VERSION 5.4 ;
NAMESCASESENSITIVE ON ;
BUSBITCHARS "[]" ;
DIVIDERCHAR "/" ;
UNITS
  DATABASE MICRONS 2000 ;
END UNITS
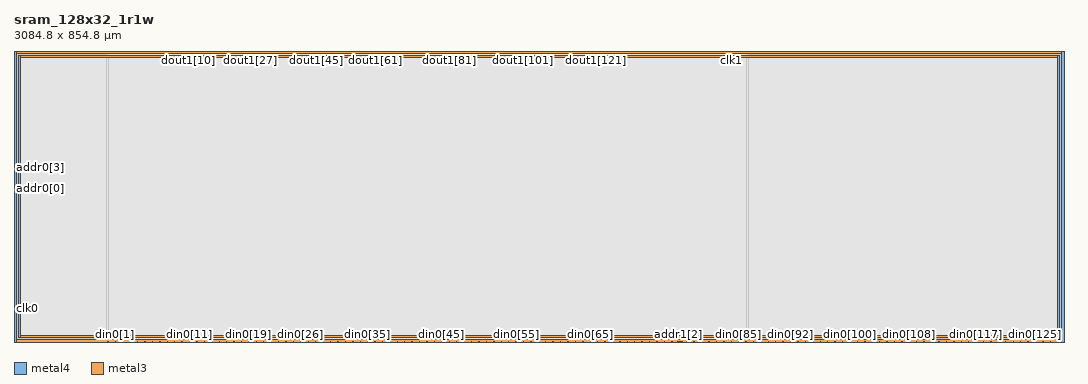
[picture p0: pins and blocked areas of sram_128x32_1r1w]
MACRO sram_128x32_1r1w
   CLASS BLOCK ;
   SIZE 3084.8 BY 854.8 ;
   SYMMETRY X Y R90 ;
   PIN din0[0]
      DIRECTION INPUT ;
      PORT
         LAYER metal4 ;
         RECT  275.4 0.0 276.6 1.2 ;
      END
   END din0[0]
   PIN din0[1]
      DIRECTION INPUT ;
      PORT
         LAYER metal4 ;
         RECT  297.2 0.0 298.4 1.2 ;
      END
   END din0[1]
   PIN din0[2]
      DIRECTION INPUT ;
      PORT
         LAYER metal4 ;
         RECT  319.0 0.0 320.2 1.2 ;
      END
   END din0[2]
   PIN din0[3]
      DIRECTION INPUT ;
      PORT
         LAYER metal4 ;
         RECT  340.8 0.0 342.0 1.2 ;
      END
   END din0[3]
   PIN din0[4]
      DIRECTION INPUT ;
      PORT
         LAYER metal4 ;
         RECT  362.6 0.0 363.8 1.2 ;
      END
   END din0[4]
   PIN din0[5]
      DIRECTION INPUT ;
      PORT
         LAYER metal4 ;
         RECT  384.4 0.0 385.6 1.2 ;
      END
   END din0[5]
   PIN din0[6]
      DIRECTION INPUT ;
      PORT
         LAYER metal4 ;
         RECT  406.2 0.0 407.4 1.2 ;
      END
   END din0[6]
   PIN din0[7]
      DIRECTION INPUT ;
      PORT
         LAYER metal4 ;
         RECT  428.0 0.0 429.2 1.2 ;
      END
   END din0[7]
   PIN din0[8]
      DIRECTION INPUT ;
      PORT
         LAYER metal4 ;
         RECT  449.8 0.0 451.0 1.2 ;
      END
   END din0[8]
   PIN din0[9]
      DIRECTION INPUT ;
      PORT
         LAYER metal4 ;
         RECT  471.6 0.0 472.8 1.2 ;
      END
   END din0[9]
   PIN din0[10]
      DIRECTION INPUT ;
      PORT
         LAYER metal4 ;
         RECT  493.4 0.0 494.6 1.2 ;
      END
   END din0[10]
   PIN din0[11]
      DIRECTION INPUT ;
      PORT
         LAYER metal4 ;
         RECT  515.2 0.0 516.4 1.2 ;
      END
   END din0[11]
   PIN din0[12]
      DIRECTION INPUT ;
      PORT
         LAYER metal4 ;
         RECT  537.0 0.0 538.2 1.2 ;
      END
   END din0[12]
   PIN din0[13]
      DIRECTION INPUT ;
      PORT
         LAYER metal4 ;
         RECT  558.8 0.0 560.0 1.2 ;
      END
   END din0[13]
   PIN din0[14]
      DIRECTION INPUT ;
      PORT
         LAYER metal4 ;
         RECT  580.6 0.0 581.8 1.2 ;
      END
   END din0[14]
   PIN din0[15]
      DIRECTION INPUT ;
      PORT
         LAYER metal4 ;
         RECT  602.4 0.0 603.6 1.2 ;
      END
   END din0[15]
   PIN din0[16]
      DIRECTION INPUT ;
      PORT
         LAYER metal4 ;
         RECT  624.2 0.0 625.4 1.2 ;
      END
   END din0[16]
   PIN din0[17]
      DIRECTION INPUT ;
      PORT
         LAYER metal4 ;
         RECT  646.0 0.0 647.2 1.2 ;
      END
   END din0[17]
   PIN din0[18]
      DIRECTION INPUT ;
      PORT
         LAYER metal4 ;
         RECT  667.8 0.0 669.0 1.2 ;
      END
   END din0[18]
   PIN din0[19]
      DIRECTION INPUT ;
      PORT
         LAYER metal4 ;
         RECT  689.6 0.0 690.8 1.2 ;
      END
   END din0[19]
   PIN din0[20]
      DIRECTION INPUT ;
      PORT
         LAYER metal4 ;
         RECT  711.4 0.0 712.6 1.2 ;
      END
   END din0[20]
   PIN din0[21]
      DIRECTION INPUT ;
      PORT
         LAYER metal4 ;
         RECT  733.2 0.0 734.4 1.2 ;
      END
   END din0[21]
   PIN din0[22]
      DIRECTION INPUT ;
      PORT
         LAYER metal4 ;
         RECT  755.0 0.0 756.2 1.2 ;
      END
   END din0[22]
   PIN din0[23]
      DIRECTION INPUT ;
      PORT
         LAYER metal4 ;
         RECT  776.8 0.0 778.0 1.2 ;
      END
   END din0[23]
   PIN din0[24]
      DIRECTION INPUT ;
      PORT
         LAYER metal4 ;
         RECT  798.6 0.0 799.8 1.2 ;
      END
   END din0[24]
   PIN din0[25]
      DIRECTION INPUT ;
      PORT
         LAYER metal4 ;
         RECT  820.4 0.0 821.6 1.2 ;
      END
   END din0[25]
   PIN din0[26]
      DIRECTION INPUT ;
      PORT
         LAYER metal4 ;
         RECT  842.2 0.0 843.4 1.2 ;
      END
   END din0[26]
   PIN din0[27]
      DIRECTION INPUT ;
      PORT
         LAYER metal4 ;
         RECT  864.0 0.0 865.2 1.2 ;
      END
   END din0[27]
   PIN din0[28]
      DIRECTION INPUT ;
      PORT
         LAYER metal4 ;
         RECT  885.8 0.0 887.0 1.2 ;
      END
   END din0[28]
   PIN din0[29]
      DIRECTION INPUT ;
      PORT
         LAYER metal4 ;
         RECT  907.6 0.0 908.8 1.2 ;
      END
   END din0[29]
   PIN din0[30]
      DIRECTION INPUT ;
      PORT
         LAYER metal4 ;
         RECT  929.4 0.0 930.6 1.2 ;
      END
   END din0[30]
   PIN din0[31]
      DIRECTION INPUT ;
      PORT
         LAYER metal4 ;
         RECT  951.2 0.0 952.4 1.2 ;
      END
   END din0[31]
   PIN din0[32]
      DIRECTION INPUT ;
      PORT
         LAYER metal4 ;
         RECT  973.0 0.0 974.2 1.2 ;
      END
   END din0[32]
   PIN din0[33]
      DIRECTION INPUT ;
      PORT
         LAYER metal4 ;
         RECT  994.8 0.0 996.0 1.2 ;
      END
   END din0[33]
   PIN din0[34]
      DIRECTION INPUT ;
      PORT
         LAYER metal4 ;
         RECT  1016.6 0.0 1017.8 1.2 ;
      END
   END din0[34]
   PIN din0[35]
      DIRECTION INPUT ;
      PORT
         LAYER metal4 ;
         RECT  1038.4 0.0 1039.6 1.2 ;
      END
   END din0[35]
   PIN din0[36]
      DIRECTION INPUT ;
      PORT
         LAYER metal4 ;
         RECT  1060.2 0.0 1061.4 1.2 ;
      END
   END din0[36]
   PIN din0[37]
      DIRECTION INPUT ;
      PORT
         LAYER metal4 ;
         RECT  1082.0 0.0 1083.2 1.2 ;
      END
   END din0[37]
   PIN din0[38]
      DIRECTION INPUT ;
      PORT
         LAYER metal4 ;
         RECT  1103.8 0.0 1105.0 1.2 ;
      END
   END din0[38]
   PIN din0[39]
      DIRECTION INPUT ;
      PORT
         LAYER metal4 ;
         RECT  1125.6 0.0 1126.8 1.2 ;
      END
   END din0[39]
   PIN din0[40]
      DIRECTION INPUT ;
      PORT
         LAYER metal4 ;
         RECT  1147.4 0.0 1148.6 1.2 ;
      END
   END din0[40]
   PIN din0[41]
      DIRECTION INPUT ;
      PORT
         LAYER metal4 ;
         RECT  1169.2 0.0 1170.4 1.2 ;
      END
   END din0[41]
   PIN din0[42]
      DIRECTION INPUT ;
      PORT
         LAYER metal4 ;
         RECT  1191.0 0.0 1192.2 1.2 ;
      END
   END din0[42]
   PIN din0[43]
      DIRECTION INPUT ;
      PORT
         LAYER metal4 ;
         RECT  1212.8 0.0 1214.0 1.2 ;
      END
   END din0[43]
   PIN din0[44]
      DIRECTION INPUT ;
      PORT
         LAYER metal4 ;
         RECT  1234.6 0.0 1235.8 1.2 ;
      END
   END din0[44]
   PIN din0[45]
      DIRECTION INPUT ;
      PORT
         LAYER metal4 ;
         RECT  1256.4 0.0 1257.6 1.2 ;
      END
   END din0[45]
   PIN din0[46]
      DIRECTION INPUT ;
      PORT
         LAYER metal4 ;
         RECT  1278.2 0.0 1279.4 1.2 ;
      END
   END din0[46]
   PIN din0[47]
      DIRECTION INPUT ;
      PORT
         LAYER metal4 ;
         RECT  1300.0 0.0 1301.2 1.2 ;
      END
   END din0[47]
   PIN din0[48]
      DIRECTION INPUT ;
      PORT
         LAYER metal4 ;
         RECT  1321.8 0.0 1323.0 1.2 ;
      END
   END din0[48]
   PIN din0[49]
      DIRECTION INPUT ;
      PORT
         LAYER metal4 ;
         RECT  1343.6 0.0 1344.8 1.2 ;
      END
   END din0[49]
   PIN din0[50]
      DIRECTION INPUT ;
      PORT
         LAYER metal4 ;
         RECT  1365.4 0.0 1366.6 1.2 ;
      END
   END din0[50]
   PIN din0[51]
      DIRECTION INPUT ;
      PORT
         LAYER metal4 ;
         RECT  1387.2 0.0 1388.4 1.2 ;
      END
   END din0[51]
   PIN din0[52]
      DIRECTION INPUT ;
      PORT
         LAYER metal4 ;
         RECT  1409.0 0.0 1410.2 1.2 ;
      END
   END din0[52]
   PIN din0[53]
      DIRECTION INPUT ;
      PORT
         LAYER metal4 ;
         RECT  1430.8 0.0 1432.0 1.2 ;
      END
   END din0[53]
   PIN din0[54]
      DIRECTION INPUT ;
      PORT
         LAYER metal4 ;
         RECT  1452.6 0.0 1453.8 1.2 ;
      END
   END din0[54]
   PIN din0[55]
      DIRECTION INPUT ;
      PORT
         LAYER metal4 ;
         RECT  1474.4 0.0 1475.6 1.2 ;
      END
   END din0[55]
   PIN din0[56]
      DIRECTION INPUT ;
      PORT
         LAYER metal4 ;
         RECT  1496.2 0.0 1497.4 1.2 ;
      END
   END din0[56]
   PIN din0[57]
      DIRECTION INPUT ;
      PORT
         LAYER metal4 ;
         RECT  1518.0 0.0 1519.2 1.2 ;
      END
   END din0[57]
   PIN din0[58]
      DIRECTION INPUT ;
      PORT
         LAYER metal4 ;
         RECT  1539.8 0.0 1541.0 1.2 ;
      END
   END din0[58]
   PIN din0[59]
      DIRECTION INPUT ;
      PORT
         LAYER metal4 ;
         RECT  1561.6 0.0 1562.8 1.2 ;
      END
   END din0[59]
   PIN din0[60]
      DIRECTION INPUT ;
      PORT
         LAYER metal4 ;
         RECT  1583.4 0.0 1584.6 1.2 ;
      END
   END din0[60]
   PIN din0[61]
      DIRECTION INPUT ;
      PORT
         LAYER metal4 ;
         RECT  1605.2 0.0 1606.4 1.2 ;
      END
   END din0[61]
   PIN din0[62]
      DIRECTION INPUT ;
      PORT
         LAYER metal4 ;
         RECT  1627.0 0.0 1628.2 1.2 ;
      END
   END din0[62]
   PIN din0[63]
      DIRECTION INPUT ;
      PORT
         LAYER metal4 ;
         RECT  1648.8 0.0 1650.0 1.2 ;
      END
   END din0[63]
   PIN din0[64]
      DIRECTION INPUT ;
      PORT
         LAYER metal4 ;
         RECT  1670.6 0.0 1671.8 1.2 ;
      END
   END din0[64]
   PIN din0[65]
      DIRECTION INPUT ;
      PORT
         LAYER metal4 ;
         RECT  1692.4 0.0 1693.6 1.2 ;
      END
   END din0[65]
   PIN din0[66]
      DIRECTION INPUT ;
      PORT
         LAYER metal4 ;
         RECT  1714.2 0.0 1715.4 1.2 ;
      END
   END din0[66]
   PIN din0[67]
      DIRECTION INPUT ;
      PORT
         LAYER metal4 ;
         RECT  1736.0 0.0 1737.2 1.2 ;
      END
   END din0[67]
   PIN din0[68]
      DIRECTION INPUT ;
      PORT
         LAYER metal4 ;
         RECT  1757.8 0.0 1759.0 1.2 ;
      END
   END din0[68]
   PIN din0[69]
      DIRECTION INPUT ;
      PORT
         LAYER metal4 ;
         RECT  1779.6 0.0 1780.8 1.2 ;
      END
   END din0[69]
   PIN din0[70]
      DIRECTION INPUT ;
      PORT
         LAYER metal4 ;
         RECT  1801.4 0.0 1802.6 1.2 ;
      END
   END din0[70]
   PIN din0[71]
      DIRECTION INPUT ;
      PORT
         LAYER metal4 ;
         RECT  1823.2 0.0 1824.4 1.2 ;
      END
   END din0[71]
   PIN din0[72]
      DIRECTION INPUT ;
      PORT
         LAYER metal4 ;
         RECT  1845.0 0.0 1846.2 1.2 ;
      END
   END din0[72]
   PIN din0[73]
      DIRECTION INPUT ;
      PORT
         LAYER metal4 ;
         RECT  1866.8 0.0 1868.0 1.2 ;
      END
   END din0[73]
   PIN din0[74]
      DIRECTION INPUT ;
      PORT
         LAYER metal4 ;
         RECT  1888.6 0.0 1889.8 1.2 ;
      END
   END din0[74]
   PIN din0[75]
      DIRECTION INPUT ;
      PORT
         LAYER metal4 ;
         RECT  1910.4 0.0 1911.6 1.2 ;
      END
   END din0[75]
   PIN din0[76]
      DIRECTION INPUT ;
      PORT
         LAYER metal4 ;
         RECT  1932.2 0.0 1933.4 1.2 ;
      END
   END din0[76]
   PIN din0[77]
      DIRECTION INPUT ;
      PORT
         LAYER metal4 ;
         RECT  1954.0 0.0 1955.2 1.2 ;
      END
   END din0[77]
   PIN din0[78]
      DIRECTION INPUT ;
      PORT
         LAYER metal4 ;
         RECT  1975.8 0.0 1977.0 1.2 ;
      END
   END din0[78]
   PIN din0[79]
      DIRECTION INPUT ;
      PORT
         LAYER metal4 ;
         RECT  1997.6 0.0 1998.8 1.2 ;
      END
   END din0[79]
   PIN din0[80]
      DIRECTION INPUT ;
      PORT
         LAYER metal4 ;
         RECT  2019.4 0.0 2020.6 1.2 ;
      END
   END din0[80]
   PIN din0[81]
      DIRECTION INPUT ;
      PORT
         LAYER metal4 ;
         RECT  2041.2 0.0 2042.4 1.2 ;
      END
   END din0[81]
   PIN din0[82]
      DIRECTION INPUT ;
      PORT
         LAYER metal4 ;
         RECT  2063.0 0.0 2064.2 1.2 ;
      END
   END din0[82]
   PIN din0[83]
      DIRECTION INPUT ;
      PORT
         LAYER metal4 ;
         RECT  2084.8 0.0 2086.0 1.2 ;
      END
   END din0[83]
   PIN din0[84]
      DIRECTION INPUT ;
      PORT
         LAYER metal4 ;
         RECT  2106.6 0.0 2107.8 1.2 ;
      END
   END din0[84]
   PIN din0[85]
      DIRECTION INPUT ;
      PORT
         LAYER metal4 ;
         RECT  2128.4 0.0 2129.6 1.2 ;
      END
   END din0[85]
   PIN din0[86]
      DIRECTION INPUT ;
      PORT
         LAYER metal4 ;
         RECT  2150.2 0.0 2151.4 1.2 ;
      END
   END din0[86]
   PIN din0[87]
      DIRECTION INPUT ;
      PORT
         LAYER metal4 ;
         RECT  2172.0 0.0 2173.2 1.2 ;
      END
   END din0[87]
   PIN din0[88]
      DIRECTION INPUT ;
      PORT
         LAYER metal4 ;
         RECT  2193.8 0.0 2195.0 1.2 ;
      END
   END din0[88]
   PIN din0[89]
      DIRECTION INPUT ;
      PORT
         LAYER metal4 ;
         RECT  2215.6 0.0 2216.8 1.2 ;
      END
   END din0[89]
   PIN din0[90]
      DIRECTION INPUT ;
      PORT
         LAYER metal4 ;
         RECT  2237.4 0.0 2238.6 1.2 ;
      END
   END din0[90]
   PIN din0[91]
      DIRECTION INPUT ;
      PORT
         LAYER metal4 ;
         RECT  2259.2 0.0 2260.4 1.2 ;
      END
   END din0[91]
   PIN din0[92]
      DIRECTION INPUT ;
      PORT
         LAYER metal4 ;
         RECT  2281.0 0.0 2282.2 1.2 ;
      END
   END din0[92]
   PIN din0[93]
      DIRECTION INPUT ;
      PORT
         LAYER metal4 ;
         RECT  2302.8 0.0 2304.0 1.2 ;
      END
   END din0[93]
   PIN din0[94]
      DIRECTION INPUT ;
      PORT
         LAYER metal4 ;
         RECT  2324.6 0.0 2325.8 1.2 ;
      END
   END din0[94]
   PIN din0[95]
      DIRECTION INPUT ;
      PORT
         LAYER metal4 ;
         RECT  2346.4 0.0 2347.6 1.2 ;
      END
   END din0[95]
   PIN din0[96]
      DIRECTION INPUT ;
      PORT
         LAYER metal4 ;
         RECT  2368.2 0.0 2369.4 1.2 ;
      END
   END din0[96]
   PIN din0[97]
      DIRECTION INPUT ;
      PORT
         LAYER metal4 ;
         RECT  2390.0 0.0 2391.2 1.2 ;
      END
   END din0[97]
   PIN din0[98]
      DIRECTION INPUT ;
      PORT
         LAYER metal4 ;
         RECT  2411.8 0.0 2413.0 1.2 ;
      END
   END din0[98]
   PIN din0[99]
      DIRECTION INPUT ;
      PORT
         LAYER metal4 ;
         RECT  2433.6 0.0 2434.8 1.2 ;
      END
   END din0[99]
   PIN din0[100]
      DIRECTION INPUT ;
      PORT
         LAYER metal4 ;
         RECT  2455.4 0.0 2456.6 1.2 ;
      END
   END din0[100]
   PIN din0[101]
      DIRECTION INPUT ;
      PORT
         LAYER metal4 ;
         RECT  2477.2 0.0 2478.4 1.2 ;
      END
   END din0[101]
   PIN din0[102]
      DIRECTION INPUT ;
      PORT
         LAYER metal4 ;
         RECT  2499.0 0.0 2500.2 1.2 ;
      END
   END din0[102]
   PIN din0[103]
      DIRECTION INPUT ;
      PORT
         LAYER metal4 ;
         RECT  2520.8 0.0 2522.0 1.2 ;
      END
   END din0[103]
   PIN din0[104]
      DIRECTION INPUT ;
      PORT
         LAYER metal4 ;
         RECT  2542.6 0.0 2543.8 1.2 ;
      END
   END din0[104]
   PIN din0[105]
      DIRECTION INPUT ;
      PORT
         LAYER metal4 ;
         RECT  2564.4 0.0 2565.6 1.2 ;
      END
   END din0[105]
   PIN din0[106]
      DIRECTION INPUT ;
      PORT
         LAYER metal4 ;
         RECT  2586.2 0.0 2587.4 1.2 ;
      END
   END din0[106]
   PIN din0[107]
      DIRECTION INPUT ;
      PORT
         LAYER metal4 ;
         RECT  2608.0 0.0 2609.2 1.2 ;
      END
   END din0[107]
   PIN din0[108]
      DIRECTION INPUT ;
      PORT
         LAYER metal4 ;
         RECT  2629.8 0.0 2631.0 1.2 ;
      END
   END din0[108]
   PIN din0[109]
      DIRECTION INPUT ;
      PORT
         LAYER metal4 ;
         RECT  2651.6 0.0 2652.8 1.2 ;
      END
   END din0[109]
   PIN din0[110]
      DIRECTION INPUT ;
      PORT
         LAYER metal4 ;
         RECT  2673.4 0.0 2674.6 1.2 ;
      END
   END din0[110]
   PIN din0[111]
      DIRECTION INPUT ;
      PORT
         LAYER metal4 ;
         RECT  2695.2 0.0 2696.4 1.2 ;
      END
   END din0[111]
   PIN din0[112]
      DIRECTION INPUT ;
      PORT
         LAYER metal4 ;
         RECT  2717.0 0.0 2718.2 1.2 ;
      END
   END din0[112]
   PIN din0[113]
      DIRECTION INPUT ;
      PORT
         LAYER metal4 ;
         RECT  2738.8 0.0 2740.0 1.2 ;
      END
   END din0[113]
   PIN din0[114]
      DIRECTION INPUT ;
      PORT
         LAYER metal4 ;
         RECT  2760.6 0.0 2761.8 1.2 ;
      END
   END din0[114]
   PIN din0[115]
      DIRECTION INPUT ;
      PORT
         LAYER metal4 ;
         RECT  2782.4 0.0 2783.6 1.2 ;
      END
   END din0[115]
   PIN din0[116]
      DIRECTION INPUT ;
      PORT
         LAYER metal4 ;
         RECT  2804.2 0.0 2805.4 1.2 ;
      END
   END din0[116]
   PIN din0[117]
      DIRECTION INPUT ;
      PORT
         LAYER metal4 ;
         RECT  2826.0 0.0 2827.2 1.2 ;
      END
   END din0[117]
   PIN din0[118]
      DIRECTION INPUT ;
      PORT
         LAYER metal4 ;
         RECT  2847.8 0.0 2849.0 1.2 ;
      END
   END din0[118]
   PIN din0[119]
      DIRECTION INPUT ;
      PORT
         LAYER metal4 ;
         RECT  2869.6 0.0 2870.8 1.2 ;
      END
   END din0[119]
   PIN din0[120]
      DIRECTION INPUT ;
      PORT
         LAYER metal4 ;
         RECT  2891.4 0.0 2892.6 1.2 ;
      END
   END din0[120]
   PIN din0[121]
      DIRECTION INPUT ;
      PORT
         LAYER metal4 ;
         RECT  2913.2 0.0 2914.4 1.2 ;
      END
   END din0[121]
   PIN din0[122]
      DIRECTION INPUT ;
      PORT
         LAYER metal4 ;
         RECT  2935.0 0.0 2936.2 1.2 ;
      END
   END din0[122]
   PIN din0[123]
      DIRECTION INPUT ;
      PORT
         LAYER metal4 ;
         RECT  2956.8 0.0 2958.0 1.2 ;
      END
   END din0[123]
   PIN din0[124]
      DIRECTION INPUT ;
      PORT
         LAYER metal4 ;
         RECT  2978.6 0.0 2979.8 1.2 ;
      END
   END din0[124]
   PIN din0[125]
      DIRECTION INPUT ;
      PORT
         LAYER metal4 ;
         RECT  3000.4 0.0 3001.6 1.2 ;
      END
   END din0[125]
   PIN din0[126]
      DIRECTION INPUT ;
      PORT
         LAYER metal4 ;
         RECT  3022.2 0.0 3023.4 1.2 ;
      END
   END din0[126]
   PIN din0[127]
      DIRECTION INPUT ;
      PORT
         LAYER metal4 ;
         RECT  3044.0 0.0 3045.2 1.2 ;
      END
   END din0[127]
   PIN addr0[0]
      DIRECTION INPUT ;
      PORT
         LAYER metal3 ;
         RECT  0.0 450.2 1.2 451.4 ;
      END
   END addr0[0]
   PIN addr0[1]
      DIRECTION INPUT ;
      PORT
         LAYER metal3 ;
         RECT  0.0 472.2 1.2 473.4 ;
      END
   END addr0[1]
   PIN addr0[2]
      DIRECTION INPUT ;
      PORT
         LAYER metal3 ;
         RECT  0.0 490.2 1.2 491.4 ;
      END
   END addr0[2]
   PIN addr0[3]
      DIRECTION INPUT ;
      PORT
         LAYER metal3 ;
         RECT  0.0 512.2 1.2 513.4 ;
      END
   END addr0[3]
   PIN addr0[4]
      DIRECTION INPUT ;
      PORT
         LAYER metal3 ;
         RECT  0.0 530.2 1.2 531.4 ;
      END
   END addr0[4]
   PIN addr1[0]
      DIRECTION INPUT ;
      PORT
         LAYER metal4 ;
         RECT  1948.8 0.0 1950.0 1.2 ;
      END
   END addr1[0]
   PIN addr1[1]
      DIRECTION INPUT ;
      PORT
         LAYER metal4 ;
         RECT  1961.8 0.0 1963.0 1.2 ;
      END
   END addr1[1]
   PIN addr1[2]
      DIRECTION INPUT ;
      PORT
         LAYER metal4 ;
         RECT  1951.4 0.0 1952.6 1.2 ;
      END
   END addr1[2]
   PIN addr1[3]
      DIRECTION INPUT ;
      PORT
         LAYER metal4 ;
         RECT  1959.2 0.0 1960.4 1.2 ;
      END
   END addr1[3]
   PIN addr1[4]
      DIRECTION INPUT ;
      PORT
         LAYER metal4 ;
         RECT  1956.6 0.0 1957.8 1.2 ;
      END
   END addr1[4]
   PIN csb0
      DIRECTION INPUT ;
      PORT
         LAYER metal3 ;
         RECT  0.0 97.0 1.2 98.2 ;
      END
   END csb0
   PIN csb1
      DIRECTION INPUT ;
      PORT
         LAYER metal4 ;
         RECT  2153.4 853.6 2154.6 854.8 ;
      END
   END csb1
   PIN clk0
      DIRECTION INPUT ;
      PORT
         LAYER metal3 ;
         RECT  0.0 99.0 1.2 100.2 ;
      END
   END clk0
   PIN clk1
      DIRECTION INPUT ;
      PORT
         LAYER metal4 ;
         RECT  2107.0 853.6 2108.2 854.8 ;
      END
   END clk1
   PIN dout1[0]
      DIRECTION OUTPUT ;
      PORT
         LAYER metal4 ;
         RECT  403.1 853.6 404.3 854.8 ;
      END
   END dout1[0]
   PIN dout1[1]
      DIRECTION OUTPUT ;
      PORT
         LAYER metal4 ;
         RECT  413.9 853.6 415.1 854.8 ;
      END
   END dout1[1]
   PIN dout1[2]
      DIRECTION OUTPUT ;
      PORT
         LAYER metal4 ;
         RECT  424.7 853.6 425.9 854.8 ;
      END
   END dout1[2]
   PIN dout1[3]
      DIRECTION OUTPUT ;
      PORT
         LAYER metal4 ;
         RECT  435.5 853.6 436.7 854.8 ;
      END
   END dout1[3]
   PIN dout1[4]
      DIRECTION OUTPUT ;
      PORT
         LAYER metal4 ;
         RECT  446.3 853.6 447.5 854.8 ;
      END
   END dout1[4]
   PIN dout1[5]
      DIRECTION OUTPUT ;
      PORT
         LAYER metal4 ;
         RECT  457.1 853.6 458.3 854.8 ;
      END
   END dout1[5]
   PIN dout1[6]
      DIRECTION OUTPUT ;
      PORT
         LAYER metal4 ;
         RECT  467.9 853.6 469.1 854.8 ;
      END
   END dout1[6]
   PIN dout1[7]
      DIRECTION OUTPUT ;
      PORT
         LAYER metal4 ;
         RECT  478.7 853.6 479.9 854.8 ;
      END
   END dout1[7]
   PIN dout1[8]
      DIRECTION OUTPUT ;
      PORT
         LAYER metal4 ;
         RECT  489.5 853.6 490.7 854.8 ;
      END
   END dout1[8]
   PIN dout1[9]
      DIRECTION OUTPUT ;
      PORT
         LAYER metal4 ;
         RECT  500.3 853.6 501.5 854.8 ;
      END
   END dout1[9]
   PIN dout1[10]
      DIRECTION OUTPUT ;
      PORT
         LAYER metal4 ;
         RECT  511.1 853.6 512.3 854.8 ;
      END
   END dout1[10]
   PIN dout1[11]
      DIRECTION OUTPUT ;
      PORT
         LAYER metal4 ;
         RECT  521.9 853.6 523.1 854.8 ;
      END
   END dout1[11]
   PIN dout1[12]
      DIRECTION OUTPUT ;
      PORT
         LAYER metal4 ;
         RECT  532.7 853.6 533.9 854.8 ;
      END
   END dout1[12]
   PIN dout1[13]
      DIRECTION OUTPUT ;
      PORT
         LAYER metal4 ;
         RECT  543.5 853.6 544.7 854.8 ;
      END
   END dout1[13]
   PIN dout1[14]
      DIRECTION OUTPUT ;
      PORT
         LAYER metal4 ;
         RECT  554.3 853.6 555.5 854.8 ;
      END
   END dout1[14]
   PIN dout1[15]
      DIRECTION OUTPUT ;
      PORT
         LAYER metal4 ;
         RECT  565.1 853.6 566.3 854.8 ;
      END
   END dout1[15]
   PIN dout1[16]
      DIRECTION OUTPUT ;
      PORT
         LAYER metal4 ;
         RECT  575.9 853.6 577.1 854.8 ;
      END
   END dout1[16]
   PIN dout1[17]
      DIRECTION OUTPUT ;
      PORT
         LAYER metal4 ;
         RECT  586.7 853.6 587.9 854.8 ;
      END
   END dout1[17]
   PIN dout1[18]
      DIRECTION OUTPUT ;
      PORT
         LAYER metal4 ;
         RECT  597.5 853.6 598.7 854.8 ;
      END
   END dout1[18]
   PIN dout1[19]
      DIRECTION OUTPUT ;
      PORT
         LAYER metal4 ;
         RECT  608.3 853.6 609.5 854.8 ;
      END
   END dout1[19]
   PIN dout1[20]
      DIRECTION OUTPUT ;
      PORT
         LAYER metal4 ;
         RECT  619.1 853.6 620.3 854.8 ;
      END
   END dout1[20]
   PIN dout1[21]
      DIRECTION OUTPUT ;
      PORT
         LAYER metal4 ;
         RECT  629.9 853.6 631.1 854.8 ;
      END
   END dout1[21]
   PIN dout1[22]
      DIRECTION OUTPUT ;
      PORT
         LAYER metal4 ;
         RECT  640.7 853.6 641.9 854.8 ;
      END
   END dout1[22]
   PIN dout1[23]
      DIRECTION OUTPUT ;
      PORT
         LAYER metal4 ;
         RECT  651.5 853.6 652.7 854.8 ;
      END
   END dout1[23]
   PIN dout1[24]
      DIRECTION OUTPUT ;
      PORT
         LAYER metal4 ;
         RECT  662.3 853.6 663.5 854.8 ;
      END
   END dout1[24]
   PIN dout1[25]
      DIRECTION OUTPUT ;
      PORT
         LAYER metal4 ;
         RECT  673.1 853.6 674.3 854.8 ;
      END
   END dout1[25]
   PIN dout1[26]
      DIRECTION OUTPUT ;
      PORT
         LAYER metal4 ;
         RECT  683.9 853.6 685.1 854.8 ;
      END
   END dout1[26]
   PIN dout1[27]
      DIRECTION OUTPUT ;
      PORT
         LAYER metal4 ;
         RECT  694.7 853.6 695.9 854.8 ;
      END
   END dout1[27]
   PIN dout1[28]
      DIRECTION OUTPUT ;
      PORT
         LAYER metal4 ;
         RECT  705.5 853.6 706.7 854.8 ;
      END
   END dout1[28]
   PIN dout1[29]
      DIRECTION OUTPUT ;
      PORT
         LAYER metal4 ;
         RECT  716.3 853.6 717.5 854.8 ;
      END
   END dout1[29]
   PIN dout1[30]
      DIRECTION OUTPUT ;
      PORT
         LAYER metal4 ;
         RECT  727.1 853.6 728.3 854.8 ;
      END
   END dout1[30]
   PIN dout1[31]
      DIRECTION OUTPUT ;
      PORT
         LAYER metal4 ;
         RECT  737.9 853.6 739.1 854.8 ;
      END
   END dout1[31]
   PIN dout1[32]
      DIRECTION OUTPUT ;
      PORT
         LAYER metal4 ;
         RECT  748.7 853.6 749.9 854.8 ;
      END
   END dout1[32]
   PIN dout1[33]
      DIRECTION OUTPUT ;
      PORT
         LAYER metal4 ;
         RECT  759.5 853.6 760.7 854.8 ;
      END
   END dout1[33]
   PIN dout1[34]
      DIRECTION OUTPUT ;
      PORT
         LAYER metal4 ;
         RECT  770.3 853.6 771.5 854.8 ;
      END
   END dout1[34]
   PIN dout1[35]
      DIRECTION OUTPUT ;
      PORT
         LAYER metal4 ;
         RECT  781.1 853.6 782.3 854.8 ;
      END
   END dout1[35]
   PIN dout1[36]
      DIRECTION OUTPUT ;
      PORT
         LAYER metal4 ;
         RECT  791.9 853.6 793.1 854.8 ;
      END
   END dout1[36]
   PIN dout1[37]
      DIRECTION OUTPUT ;
      PORT
         LAYER metal4 ;
         RECT  802.7 853.6 803.9 854.8 ;
      END
   END dout1[37]
   PIN dout1[38]
      DIRECTION OUTPUT ;
      PORT
         LAYER metal4 ;
         RECT  813.5 853.6 814.7 854.8 ;
      END
   END dout1[38]
   PIN dout1[39]
      DIRECTION OUTPUT ;
      PORT
         LAYER metal4 ;
         RECT  824.3 853.6 825.5 854.8 ;
      END
   END dout1[39]
   PIN dout1[40]
      DIRECTION OUTPUT ;
      PORT
         LAYER metal4 ;
         RECT  835.1 853.6 836.3 854.8 ;
      END
   END dout1[40]
   PIN dout1[41]
      DIRECTION OUTPUT ;
      PORT
         LAYER metal4 ;
         RECT  845.9 853.6 847.1 854.8 ;
      END
   END dout1[41]
   PIN dout1[42]
      DIRECTION OUTPUT ;
      PORT
         LAYER metal4 ;
         RECT  856.7 853.6 857.9 854.8 ;
      END
   END dout1[42]
   PIN dout1[43]
      DIRECTION OUTPUT ;
      PORT
         LAYER metal4 ;
         RECT  867.5 853.6 868.7 854.8 ;
      END
   END dout1[43]
   PIN dout1[44]
      DIRECTION OUTPUT ;
      PORT
         LAYER metal4 ;
         RECT  878.3 853.6 879.5 854.8 ;
      END
   END dout1[44]
   PIN dout1[45]
      DIRECTION OUTPUT ;
      PORT
         LAYER metal4 ;
         RECT  889.1 853.6 890.3 854.8 ;
      END
   END dout1[45]
   PIN dout1[46]
      DIRECTION OUTPUT ;
      PORT
         LAYER metal4 ;
         RECT  899.9 853.6 901.1 854.8 ;
      END
   END dout1[46]
   PIN dout1[47]
      DIRECTION OUTPUT ;
      PORT
         LAYER metal4 ;
         RECT  910.7 853.6 911.9 854.8 ;
      END
   END dout1[47]
   PIN dout1[48]
      DIRECTION OUTPUT ;
      PORT
         LAYER metal4 ;
         RECT  921.5 853.6 922.7 854.8 ;
      END
   END dout1[48]
   PIN dout1[49]
      DIRECTION OUTPUT ;
      PORT
         LAYER metal4 ;
         RECT  932.3 853.6 933.5 854.8 ;
      END
   END dout1[49]
   PIN dout1[50]
      DIRECTION OUTPUT ;
      PORT
         LAYER metal4 ;
         RECT  943.1 853.6 944.3 854.8 ;
      END
   END dout1[50]
   PIN dout1[51]
      DIRECTION OUTPUT ;
      PORT
         LAYER metal4 ;
         RECT  953.9 853.6 955.1 854.8 ;
      END
   END dout1[51]
   PIN dout1[52]
      DIRECTION OUTPUT ;
      PORT
         LAYER metal4 ;
         RECT  964.7 853.6 965.9 854.8 ;
      END
   END dout1[52]
   PIN dout1[53]
      DIRECTION OUTPUT ;
      PORT
         LAYER metal4 ;
         RECT  975.5 853.6 976.7 854.8 ;
      END
   END dout1[53]
   PIN dout1[54]
      DIRECTION OUTPUT ;
      PORT
         LAYER metal4 ;
         RECT  986.3 853.6 987.5 854.8 ;
      END
   END dout1[54]
   PIN dout1[55]
      DIRECTION OUTPUT ;
      PORT
         LAYER metal4 ;
         RECT  997.1 853.6 998.3 854.8 ;
      END
   END dout1[55]
   PIN dout1[56]
      DIRECTION OUTPUT ;
      PORT
         LAYER metal4 ;
         RECT  1007.9 853.6 1009.1 854.8 ;
      END
   END dout1[56]
   PIN dout1[57]
      DIRECTION OUTPUT ;
      PORT
         LAYER metal4 ;
         RECT  1018.7 853.6 1019.9 854.8 ;
      END
   END dout1[57]
   PIN dout1[58]
      DIRECTION OUTPUT ;
      PORT
         LAYER metal4 ;
         RECT  1029.5 853.6 1030.7 854.8 ;
      END
   END dout1[58]
   PIN dout1[59]
      DIRECTION OUTPUT ;
      PORT
         LAYER metal4 ;
         RECT  1040.3 853.6 1041.5 854.8 ;
      END
   END dout1[59]
   PIN dout1[60]
      DIRECTION OUTPUT ;
      PORT
         LAYER metal4 ;
         RECT  1051.1 853.6 1052.3 854.8 ;
      END
   END dout1[60]
   PIN dout1[61]
      DIRECTION OUTPUT ;
      PORT
         LAYER metal4 ;
         RECT  1061.9 853.6 1063.1 854.8 ;
      END
   END dout1[61]
   PIN dout1[62]
      DIRECTION OUTPUT ;
      PORT
         LAYER metal4 ;
         RECT  1072.7 853.6 1073.9 854.8 ;
      END
   END dout1[62]
   PIN dout1[63]
      DIRECTION OUTPUT ;
      PORT
         LAYER metal4 ;
         RECT  1083.5 853.6 1084.7 854.8 ;
      END
   END dout1[63]
   PIN dout1[64]
      DIRECTION OUTPUT ;
      PORT
         LAYER metal4 ;
         RECT  1094.3 853.6 1095.5 854.8 ;
      END
   END dout1[64]
   PIN dout1[65]
      DIRECTION OUTPUT ;
      PORT
         LAYER metal4 ;
         RECT  1105.1 853.6 1106.3 854.8 ;
      END
   END dout1[65]
   PIN dout1[66]
      DIRECTION OUTPUT ;
      PORT
         LAYER metal4 ;
         RECT  1115.9 853.6 1117.1 854.8 ;
      END
   END dout1[66]
   PIN dout1[67]
      DIRECTION OUTPUT ;
      PORT
         LAYER metal4 ;
         RECT  1126.7 853.6 1127.9 854.8 ;
      END
   END dout1[67]
   PIN dout1[68]
      DIRECTION OUTPUT ;
      PORT
         LAYER metal4 ;
         RECT  1137.5 853.6 1138.7 854.8 ;
      END
   END dout1[68]
   PIN dout1[69]
      DIRECTION OUTPUT ;
      PORT
         LAYER metal4 ;
         RECT  1148.3 853.6 1149.5 854.8 ;
      END
   END dout1[69]
   PIN dout1[70]
      DIRECTION OUTPUT ;
      PORT
         LAYER metal4 ;
         RECT  1159.1 853.6 1160.3 854.8 ;
      END
   END dout1[70]
   PIN dout1[71]
      DIRECTION OUTPUT ;
      PORT
         LAYER metal4 ;
         RECT  1169.9 853.6 1171.1 854.8 ;
      END
   END dout1[71]
   PIN dout1[72]
      DIRECTION OUTPUT ;
      PORT
         LAYER metal4 ;
         RECT  1180.7 853.6 1181.9 854.8 ;
      END
   END dout1[72]
   PIN dout1[73]
      DIRECTION OUTPUT ;
      PORT
         LAYER metal4 ;
         RECT  1191.5 853.6 1192.7 854.8 ;
      END
   END dout1[73]
   PIN dout1[74]
      DIRECTION OUTPUT ;
      PORT
         LAYER metal4 ;
         RECT  1202.3 853.6 1203.5 854.8 ;
      END
   END dout1[74]
   PIN dout1[75]
      DIRECTION OUTPUT ;
      PORT
         LAYER metal4 ;
         RECT  1213.1 853.6 1214.3 854.8 ;
      END
   END dout1[75]
   PIN dout1[76]
      DIRECTION OUTPUT ;
      PORT
         LAYER metal4 ;
         RECT  1223.9 853.6 1225.1 854.8 ;
      END
   END dout1[76]
   PIN dout1[77]
      DIRECTION OUTPUT ;
      PORT
         LAYER metal4 ;
         RECT  1234.7 853.6 1235.9 854.8 ;
      END
   END dout1[77]
   PIN dout1[78]
      DIRECTION OUTPUT ;
      PORT
         LAYER metal4 ;
         RECT  1245.5 853.6 1246.7 854.8 ;
      END
   END dout1[78]
   PIN dout1[79]
      DIRECTION OUTPUT ;
      PORT
         LAYER metal4 ;
         RECT  1256.3 853.6 1257.5 854.8 ;
      END
   END dout1[79]
   PIN dout1[80]
      DIRECTION OUTPUT ;
      PORT
         LAYER metal4 ;
         RECT  1267.1 853.6 1268.3 854.8 ;
      END
   END dout1[80]
   PIN dout1[81]
      DIRECTION OUTPUT ;
      PORT
         LAYER metal4 ;
         RECT  1277.9 853.6 1279.1 854.8 ;
      END
   END dout1[81]
   PIN dout1[82]
      DIRECTION OUTPUT ;
      PORT
         LAYER metal4 ;
         RECT  1288.7 853.6 1289.9 854.8 ;
      END
   END dout1[82]
   PIN dout1[83]
      DIRECTION OUTPUT ;
      PORT
         LAYER metal4 ;
         RECT  1299.5 853.6 1300.7 854.8 ;
      END
   END dout1[83]
   PIN dout1[84]
      DIRECTION OUTPUT ;
      PORT
         LAYER metal4 ;
         RECT  1310.3 853.6 1311.5 854.8 ;
      END
   END dout1[84]
   PIN dout1[85]
      DIRECTION OUTPUT ;
      PORT
         LAYER metal4 ;
         RECT  1321.1 853.6 1322.3 854.8 ;
      END
   END dout1[85]
   PIN dout1[86]
      DIRECTION OUTPUT ;
      PORT
         LAYER metal4 ;
         RECT  1331.9 853.6 1333.1 854.8 ;
      END
   END dout1[86]
   PIN dout1[87]
      DIRECTION OUTPUT ;
      PORT
         LAYER metal4 ;
         RECT  1342.7 853.6 1343.9 854.8 ;
      END
   END dout1[87]
   PIN dout1[88]
      DIRECTION OUTPUT ;
      PORT
         LAYER metal4 ;
         RECT  1353.5 853.6 1354.7 854.8 ;
      END
   END dout1[88]
   PIN dout1[89]
      DIRECTION OUTPUT ;
      PORT
         LAYER metal4 ;
         RECT  1364.3 853.6 1365.5 854.8 ;
      END
   END dout1[89]
   PIN dout1[90]
      DIRECTION OUTPUT ;
      PORT
         LAYER metal4 ;
         RECT  1375.1 853.6 1376.3 854.8 ;
      END
   END dout1[90]
   PIN dout1[91]
      DIRECTION OUTPUT ;
      PORT
         LAYER metal4 ;
         RECT  1385.9 853.6 1387.1 854.8 ;
      END
   END dout1[91]
   PIN dout1[92]
      DIRECTION OUTPUT ;
      PORT
         LAYER metal4 ;
         RECT  1396.7 853.6 1397.9 854.8 ;
      END
   END dout1[92]
   PIN dout1[93]
      DIRECTION OUTPUT ;
      PORT
         LAYER metal4 ;
         RECT  1407.5 853.6 1408.7 854.8 ;
      END
   END dout1[93]
   PIN dout1[94]
      DIRECTION OUTPUT ;
      PORT
         LAYER metal4 ;
         RECT  1418.3 853.6 1419.5 854.8 ;
      END
   END dout1[94]
   PIN dout1[95]
      DIRECTION OUTPUT ;
      PORT
         LAYER metal4 ;
         RECT  1429.1 853.6 1430.3 854.8 ;
      END
   END dout1[95]
   PIN dout1[96]
      DIRECTION OUTPUT ;
      PORT
         LAYER metal4 ;
         RECT  1439.9 853.6 1441.1 854.8 ;
      END
   END dout1[96]
   PIN dout1[97]
      DIRECTION OUTPUT ;
      PORT
         LAYER metal4 ;
         RECT  1450.7 853.6 1451.9 854.8 ;
      END
   END dout1[97]
   PIN dout1[98]
      DIRECTION OUTPUT ;
      PORT
         LAYER metal4 ;
         RECT  1461.5 853.6 1462.7 854.8 ;
      END
   END dout1[98]
   PIN dout1[99]
      DIRECTION OUTPUT ;
      PORT
         LAYER metal4 ;
         RECT  1472.3 853.6 1473.5 854.8 ;
      END
   END dout1[99]
   PIN dout1[100]
      DIRECTION OUTPUT ;
      PORT
         LAYER metal4 ;
         RECT  1483.1 853.6 1484.3 854.8 ;
      END
   END dout1[100]
   PIN dout1[101]
      DIRECTION OUTPUT ;
      PORT
         LAYER metal4 ;
         RECT  1493.9 853.6 1495.1 854.8 ;
      END
   END dout1[101]
   PIN dout1[102]
      DIRECTION OUTPUT ;
      PORT
         LAYER metal4 ;
         RECT  1504.7 853.6 1505.9 854.8 ;
      END
   END dout1[102]
   PIN dout1[103]
      DIRECTION OUTPUT ;
      PORT
         LAYER metal4 ;
         RECT  1515.5 853.6 1516.7 854.8 ;
      END
   END dout1[103]
   PIN dout1[104]
      DIRECTION OUTPUT ;
      PORT
         LAYER metal4 ;
         RECT  1526.3 853.6 1527.5 854.8 ;
      END
   END dout1[104]
   PIN dout1[105]
      DIRECTION OUTPUT ;
      PORT
         LAYER metal4 ;
         RECT  1537.1 853.6 1538.3 854.8 ;
      END
   END dout1[105]
   PIN dout1[106]
      DIRECTION OUTPUT ;
      PORT
         LAYER metal4 ;
         RECT  1547.9 853.6 1549.1 854.8 ;
      END
   END dout1[106]
   PIN dout1[107]
      DIRECTION OUTPUT ;
      PORT
         LAYER metal4 ;
         RECT  1558.7 853.6 1559.9 854.8 ;
      END
   END dout1[107]
   PIN dout1[108]
      DIRECTION OUTPUT ;
      PORT
         LAYER metal4 ;
         RECT  1569.5 853.6 1570.7 854.8 ;
      END
   END dout1[108]
   PIN dout1[109]
      DIRECTION OUTPUT ;
      PORT
         LAYER metal4 ;
         RECT  1580.3 853.6 1581.5 854.8 ;
      END
   END dout1[109]
   PIN dout1[110]
      DIRECTION OUTPUT ;
      PORT
         LAYER metal4 ;
         RECT  1591.1 853.6 1592.3 854.8 ;
      END
   END dout1[110]
   PIN dout1[111]
      DIRECTION OUTPUT ;
      PORT
         LAYER metal4 ;
         RECT  1601.9 853.6 1603.1 854.8 ;
      END
   END dout1[111]
   PIN dout1[112]
      DIRECTION OUTPUT ;
      PORT
         LAYER metal4 ;
         RECT  1612.7 853.6 1613.9 854.8 ;
      END
   END dout1[112]
   PIN dout1[113]
      DIRECTION OUTPUT ;
      PORT
         LAYER metal4 ;
         RECT  1623.5 853.6 1624.7 854.8 ;
      END
   END dout1[113]
   PIN dout1[114]
      DIRECTION OUTPUT ;
      PORT
         LAYER metal4 ;
         RECT  1634.3 853.6 1635.5 854.8 ;
      END
   END dout1[114]
   PIN dout1[115]
      DIRECTION OUTPUT ;
      PORT
         LAYER metal4 ;
         RECT  1645.1 853.6 1646.3 854.8 ;
      END
   END dout1[115]
   PIN dout1[116]
      DIRECTION OUTPUT ;
      PORT
         LAYER metal4 ;
         RECT  1655.9 853.6 1657.1 854.8 ;
      END
   END dout1[116]
   PIN dout1[117]
      DIRECTION OUTPUT ;
      PORT
         LAYER metal4 ;
         RECT  1666.7 853.6 1667.9 854.8 ;
      END
   END dout1[117]
   PIN dout1[118]
      DIRECTION OUTPUT ;
      PORT
         LAYER metal4 ;
         RECT  1677.5 853.6 1678.7 854.8 ;
      END
   END dout1[118]
   PIN dout1[119]
      DIRECTION OUTPUT ;
      PORT
         LAYER metal4 ;
         RECT  1688.3 853.6 1689.5 854.8 ;
      END
   END dout1[119]
   PIN dout1[120]
      DIRECTION OUTPUT ;
      PORT
         LAYER metal4 ;
         RECT  1699.1 853.6 1700.3 854.8 ;
      END
   END dout1[120]
   PIN dout1[121]
      DIRECTION OUTPUT ;
      PORT
         LAYER metal4 ;
         RECT  1709.9 853.6 1711.1 854.8 ;
      END
   END dout1[121]
   PIN dout1[122]
      DIRECTION OUTPUT ;
      PORT
         LAYER metal4 ;
         RECT  1720.7 853.6 1721.9 854.8 ;
      END
   END dout1[122]
   PIN dout1[123]
      DIRECTION OUTPUT ;
      PORT
         LAYER metal4 ;
         RECT  1731.5 853.6 1732.7 854.8 ;
      END
   END dout1[123]
   PIN dout1[124]
      DIRECTION OUTPUT ;
      PORT
         LAYER metal4 ;
         RECT  1742.3 853.6 1743.5 854.8 ;
      END
   END dout1[124]
   PIN dout1[125]
      DIRECTION OUTPUT ;
      PORT
         LAYER metal4 ;
         RECT  1753.1 853.6 1754.3 854.8 ;
      END
   END dout1[125]
   PIN dout1[126]
      DIRECTION OUTPUT ;
      PORT
         LAYER metal4 ;
         RECT  1763.9 853.6 1765.1 854.8 ;
      END
   END dout1[126]
   PIN dout1[127]
      DIRECTION OUTPUT ;
      PORT
         LAYER metal4 ;
         RECT  1774.7 853.6 1775.9 854.8 ;
      END
   END dout1[127]
   PIN vdd
      DIRECTION INOUT ;
      USE POWER ; 
      SHAPE ABUTMENT ; 
      PORT
         LAYER metal3 ;
         RECT  0.0 848.8 3084.8 854.8 ;
         LAYER metal4 ;
         RECT  0.0 0.0 6.0 854.8 ;
         LAYER metal3 ;
         RECT  0.0 0.0 3084.8 6.0 ;
         LAYER metal4 ;
         RECT  3078.8 0.0 3084.8 854.8 ;
      END
   END vdd
   PIN gnd
      DIRECTION INOUT ;
      USE GROUND ; 
      SHAPE ABUTMENT ; 
      PORT
         LAYER metal4 ;
         RECT  3066.8 12.0 3072.8 842.8 ;
         LAYER metal3 ;
         RECT  12.0 836.8 3072.8 842.8 ;
         LAYER metal3 ;
         RECT  12.0 12.0 3072.8 18.0 ;
         LAYER metal4 ;
         RECT  12.0 12.0 18.0 842.8 ;
      END
   END gnd
   OBS
   LAYER  metal1 ;
      RECT  1.4 1.4 3083.4 853.4 ;
   LAYER  metal2 ;
      RECT  1.4 1.4 3083.4 853.4 ;
   LAYER  metal3 ;
      RECT  2.4 449.0 3083.4 452.6 ;
      RECT  1.4 452.6 2.4 471.0 ;
      RECT  1.4 474.6 2.4 489.0 ;
      RECT  1.4 492.6 2.4 511.0 ;
      RECT  1.4 514.6 2.4 529.0 ;
      RECT  1.4 101.4 2.4 449.0 ;
      RECT  1.4 532.6 2.4 847.6 ;
      RECT  1.4 7.2 2.4 95.8 ;
      RECT  2.4 452.6 10.8 835.6 ;
      RECT  2.4 835.6 10.8 844.0 ;
      RECT  2.4 844.0 10.8 847.6 ;
      RECT  10.8 452.6 3074.0 835.6 ;
      RECT  10.8 844.0 3074.0 847.6 ;
      RECT  3074.0 452.6 3083.4 835.6 ;
      RECT  3074.0 835.6 3083.4 844.0 ;
      RECT  3074.0 844.0 3083.4 847.6 ;
      RECT  2.4 7.2 10.8 10.8 ;
      RECT  2.4 10.8 10.8 19.2 ;
      RECT  2.4 19.2 10.8 449.0 ;
      RECT  10.8 7.2 3074.0 10.8 ;
      RECT  10.8 19.2 3074.0 449.0 ;
      RECT  3074.0 7.2 3083.4 10.8 ;
      RECT  3074.0 10.8 3083.4 19.2 ;
      RECT  3074.0 19.2 3083.4 449.0 ;
   LAYER  metal4 ;
      RECT  273.0 3.6 279.0 853.4 ;
      RECT  279.0 1.4 294.8 3.6 ;
      RECT  300.8 1.4 316.6 3.6 ;
      RECT  322.6 1.4 338.4 3.6 ;
      RECT  344.4 1.4 360.2 3.6 ;
      RECT  366.2 1.4 382.0 3.6 ;
      RECT  388.0 1.4 403.8 3.6 ;
      RECT  409.8 1.4 425.6 3.6 ;
      RECT  431.6 1.4 447.4 3.6 ;
      RECT  453.4 1.4 469.2 3.6 ;
      RECT  475.2 1.4 491.0 3.6 ;
      RECT  497.0 1.4 512.8 3.6 ;
      RECT  518.8 1.4 534.6 3.6 ;
      RECT  540.6 1.4 556.4 3.6 ;
      RECT  562.4 1.4 578.2 3.6 ;
      RECT  584.2 1.4 600.0 3.6 ;
      RECT  606.0 1.4 621.8 3.6 ;
      RECT  627.8 1.4 643.6 3.6 ;
      RECT  649.6 1.4 665.4 3.6 ;
      RECT  671.4 1.4 687.2 3.6 ;
      RECT  693.2 1.4 709.0 3.6 ;
      RECT  715.0 1.4 730.8 3.6 ;
      RECT  736.8 1.4 752.6 3.6 ;
      RECT  758.6 1.4 774.4 3.6 ;
      RECT  780.4 1.4 796.2 3.6 ;
      RECT  802.2 1.4 818.0 3.6 ;
      RECT  824.0 1.4 839.8 3.6 ;
      RECT  845.8 1.4 861.6 3.6 ;
      RECT  867.6 1.4 883.4 3.6 ;
      RECT  889.4 1.4 905.2 3.6 ;
      RECT  911.2 1.4 927.0 3.6 ;
      RECT  933.0 1.4 948.8 3.6 ;
      RECT  954.8 1.4 970.6 3.6 ;
      RECT  976.6 1.4 992.4 3.6 ;
      RECT  998.4 1.4 1014.2 3.6 ;
      RECT  1020.2 1.4 1036.0 3.6 ;
      RECT  1042.0 1.4 1057.8 3.6 ;
      RECT  1063.8 1.4 1079.6 3.6 ;
      RECT  1085.6 1.4 1101.4 3.6 ;
      RECT  1107.4 1.4 1123.2 3.6 ;
      RECT  1129.2 1.4 1145.0 3.6 ;
      RECT  1151.0 1.4 1166.8 3.6 ;
      RECT  1172.8 1.4 1188.6 3.6 ;
      RECT  1194.6 1.4 1210.4 3.6 ;
      RECT  1216.4 1.4 1232.2 3.6 ;
      RECT  1238.2 1.4 1254.0 3.6 ;
      RECT  1260.0 1.4 1275.8 3.6 ;
      RECT  1281.8 1.4 1297.6 3.6 ;
      RECT  1303.6 1.4 1319.4 3.6 ;
      RECT  1325.4 1.4 1341.2 3.6 ;
      RECT  1347.2 1.4 1363.0 3.6 ;
      RECT  1369.0 1.4 1384.8 3.6 ;
      RECT  1390.8 1.4 1406.6 3.6 ;
      RECT  1412.6 1.4 1428.4 3.6 ;
      RECT  1434.4 1.4 1450.2 3.6 ;
      RECT  1456.2 1.4 1472.0 3.6 ;
      RECT  1478.0 1.4 1493.8 3.6 ;
      RECT  1499.8 1.4 1515.6 3.6 ;
      RECT  1521.6 1.4 1537.4 3.6 ;
      RECT  1543.4 1.4 1559.2 3.6 ;
      RECT  1565.2 1.4 1581.0 3.6 ;
      RECT  1587.0 1.4 1602.8 3.6 ;
      RECT  1608.8 1.4 1624.6 3.6 ;
      RECT  1630.6 1.4 1646.4 3.6 ;
      RECT  1652.4 1.4 1668.2 3.6 ;
      RECT  1674.2 1.4 1690.0 3.6 ;
      RECT  1696.0 1.4 1711.8 3.6 ;
      RECT  1717.8 1.4 1733.6 3.6 ;
      RECT  1739.6 1.4 1755.4 3.6 ;
      RECT  1761.4 1.4 1777.2 3.6 ;
      RECT  1783.2 1.4 1799.0 3.6 ;
      RECT  1805.0 1.4 1820.8 3.6 ;
      RECT  1826.8 1.4 1842.6 3.6 ;
      RECT  1848.6 1.4 1864.4 3.6 ;
      RECT  1870.4 1.4 1886.2 3.6 ;
      RECT  1892.2 1.4 1908.0 3.6 ;
      RECT  1914.0 1.4 1929.8 3.6 ;
      RECT  1979.4 1.4 1995.2 3.6 ;
      RECT  2001.2 1.4 2017.0 3.6 ;
      RECT  2023.0 1.4 2038.8 3.6 ;
      RECT  2044.8 1.4 2060.6 3.6 ;
      RECT  2066.6 1.4 2082.4 3.6 ;
      RECT  2088.4 1.4 2104.2 3.6 ;
      RECT  2110.2 1.4 2126.0 3.6 ;
      RECT  2132.0 1.4 2147.8 3.6 ;
      RECT  2153.8 1.4 2169.6 3.6 ;
      RECT  2175.6 1.4 2191.4 3.6 ;
      RECT  2197.4 1.4 2213.2 3.6 ;
      RECT  2219.2 1.4 2235.0 3.6 ;
      RECT  2241.0 1.4 2256.8 3.6 ;
      RECT  2262.8 1.4 2278.6 3.6 ;
      RECT  2284.6 1.4 2300.4 3.6 ;
      RECT  2306.4 1.4 2322.2 3.6 ;
      RECT  2328.2 1.4 2344.0 3.6 ;
      RECT  2350.0 1.4 2365.8 3.6 ;
      RECT  2371.8 1.4 2387.6 3.6 ;
      RECT  2393.6 1.4 2409.4 3.6 ;
      RECT  2415.4 1.4 2431.2 3.6 ;
      RECT  2437.2 1.4 2453.0 3.6 ;
      RECT  2459.0 1.4 2474.8 3.6 ;
      RECT  2480.8 1.4 2496.6 3.6 ;
      RECT  2502.6 1.4 2518.4 3.6 ;
      RECT  2524.4 1.4 2540.2 3.6 ;
      RECT  2546.2 1.4 2562.0 3.6 ;
      RECT  2568.0 1.4 2583.8 3.6 ;
      RECT  2589.8 1.4 2605.6 3.6 ;
      RECT  2611.6 1.4 2627.4 3.6 ;
      RECT  2633.4 1.4 2649.2 3.6 ;
      RECT  2655.2 1.4 2671.0 3.6 ;
      RECT  2677.0 1.4 2692.8 3.6 ;
      RECT  2698.8 1.4 2714.6 3.6 ;
      RECT  2720.6 1.4 2736.4 3.6 ;
      RECT  2742.4 1.4 2758.2 3.6 ;
      RECT  2764.2 1.4 2780.0 3.6 ;
      RECT  2786.0 1.4 2801.8 3.6 ;
      RECT  2807.8 1.4 2823.6 3.6 ;
      RECT  2829.6 1.4 2845.4 3.6 ;
      RECT  2851.4 1.4 2867.2 3.6 ;
      RECT  2873.2 1.4 2889.0 3.6 ;
      RECT  2895.0 1.4 2910.8 3.6 ;
      RECT  2916.8 1.4 2932.6 3.6 ;
      RECT  2938.6 1.4 2954.4 3.6 ;
      RECT  2960.4 1.4 2976.2 3.6 ;
      RECT  2982.2 1.4 2998.0 3.6 ;
      RECT  3004.0 1.4 3019.8 3.6 ;
      RECT  3025.8 1.4 3041.6 3.6 ;
      RECT  1935.8 1.4 1946.4 3.6 ;
      RECT  1965.4 1.4 1973.4 3.6 ;
      RECT  279.0 3.6 2151.0 851.2 ;
      RECT  2151.0 3.6 2157.0 851.2 ;
      RECT  2110.6 851.2 2151.0 853.4 ;
      RECT  279.0 851.2 400.7 853.4 ;
      RECT  406.7 851.2 411.5 853.4 ;
      RECT  417.5 851.2 422.3 853.4 ;
      RECT  428.3 851.2 433.1 853.4 ;
      RECT  439.1 851.2 443.9 853.4 ;
      RECT  449.9 851.2 454.7 853.4 ;
      RECT  460.7 851.2 465.5 853.4 ;
      RECT  471.5 851.2 476.3 853.4 ;
      RECT  482.3 851.2 487.1 853.4 ;
      RECT  493.1 851.2 497.9 853.4 ;
      RECT  503.9 851.2 508.7 853.4 ;
      RECT  514.7 851.2 519.5 853.4 ;
      RECT  525.5 851.2 530.3 853.4 ;
      RECT  536.3 851.2 541.1 853.4 ;
      RECT  547.1 851.2 551.9 853.4 ;
      RECT  557.9 851.2 562.7 853.4 ;
      RECT  568.7 851.2 573.5 853.4 ;
      RECT  579.5 851.2 584.3 853.4 ;
      RECT  590.3 851.2 595.1 853.4 ;
      RECT  601.1 851.2 605.9 853.4 ;
      RECT  611.9 851.2 616.7 853.4 ;
      RECT  622.7 851.2 627.5 853.4 ;
      RECT  633.5 851.2 638.3 853.4 ;
      RECT  644.3 851.2 649.1 853.4 ;
      RECT  655.1 851.2 659.9 853.4 ;
      RECT  665.9 851.2 670.7 853.4 ;
      RECT  676.7 851.2 681.5 853.4 ;
      RECT  687.5 851.2 692.3 853.4 ;
      RECT  698.3 851.2 703.1 853.4 ;
      RECT  709.1 851.2 713.9 853.4 ;
      RECT  719.9 851.2 724.7 853.4 ;
      RECT  730.7 851.2 735.5 853.4 ;
      RECT  741.5 851.2 746.3 853.4 ;
      RECT  752.3 851.2 757.1 853.4 ;
      RECT  763.1 851.2 767.9 853.4 ;
      RECT  773.9 851.2 778.7 853.4 ;
      RECT  784.7 851.2 789.5 853.4 ;
      RECT  795.5 851.2 800.3 853.4 ;
      RECT  806.3 851.2 811.1 853.4 ;
      RECT  817.1 851.2 821.9 853.4 ;
      RECT  827.9 851.2 832.7 853.4 ;
      RECT  838.7 851.2 843.5 853.4 ;
      RECT  849.5 851.2 854.3 853.4 ;
      RECT  860.3 851.2 865.1 853.4 ;
      RECT  871.1 851.2 875.9 853.4 ;
      RECT  881.9 851.2 886.7 853.4 ;
      RECT  892.7 851.2 897.5 853.4 ;
      RECT  903.5 851.2 908.3 853.4 ;
      RECT  914.3 851.2 919.1 853.4 ;
      RECT  925.1 851.2 929.9 853.4 ;
      RECT  935.9 851.2 940.7 853.4 ;
      RECT  946.7 851.2 951.5 853.4 ;
      RECT  957.5 851.2 962.3 853.4 ;
      RECT  968.3 851.2 973.1 853.4 ;
      RECT  979.1 851.2 983.9 853.4 ;
      RECT  989.9 851.2 994.7 853.4 ;
      RECT  1000.7 851.2 1005.5 853.4 ;
      RECT  1011.5 851.2 1016.3 853.4 ;
      RECT  1022.3 851.2 1027.1 853.4 ;
      RECT  1033.1 851.2 1037.9 853.4 ;
      RECT  1043.9 851.2 1048.7 853.4 ;
      RECT  1054.7 851.2 1059.5 853.4 ;
      RECT  1065.5 851.2 1070.3 853.4 ;
      RECT  1076.3 851.2 1081.1 853.4 ;
      RECT  1087.1 851.2 1091.9 853.4 ;
      RECT  1097.9 851.2 1102.7 853.4 ;
      RECT  1108.7 851.2 1113.5 853.4 ;
      RECT  1119.5 851.2 1124.3 853.4 ;
      RECT  1130.3 851.2 1135.1 853.4 ;
      RECT  1141.1 851.2 1145.9 853.4 ;
      RECT  1151.9 851.2 1156.7 853.4 ;
      RECT  1162.7 851.2 1167.5 853.4 ;
      RECT  1173.5 851.2 1178.3 853.4 ;
      RECT  1184.3 851.2 1189.1 853.4 ;
      RECT  1195.1 851.2 1199.9 853.4 ;
      RECT  1205.9 851.2 1210.7 853.4 ;
      RECT  1216.7 851.2 1221.5 853.4 ;
      RECT  1227.5 851.2 1232.3 853.4 ;
      RECT  1238.3 851.2 1243.1 853.4 ;
      RECT  1249.1 851.2 1253.9 853.4 ;
      RECT  1259.9 851.2 1264.7 853.4 ;
      RECT  1270.7 851.2 1275.5 853.4 ;
      RECT  1281.5 851.2 1286.3 853.4 ;
      RECT  1292.3 851.2 1297.1 853.4 ;
      RECT  1303.1 851.2 1307.9 853.4 ;
      RECT  1313.9 851.2 1318.7 853.4 ;
      RECT  1324.7 851.2 1329.5 853.4 ;
      RECT  1335.5 851.2 1340.3 853.4 ;
      RECT  1346.3 851.2 1351.1 853.4 ;
      RECT  1357.1 851.2 1361.9 853.4 ;
      RECT  1367.9 851.2 1372.7 853.4 ;
      RECT  1378.7 851.2 1383.5 853.4 ;
      RECT  1389.5 851.2 1394.3 853.4 ;
      RECT  1400.3 851.2 1405.1 853.4 ;
      RECT  1411.1 851.2 1415.9 853.4 ;
      RECT  1421.9 851.2 1426.7 853.4 ;
      RECT  1432.7 851.2 1437.5 853.4 ;
      RECT  1443.5 851.2 1448.3 853.4 ;
      RECT  1454.3 851.2 1459.1 853.4 ;
      RECT  1465.1 851.2 1469.9 853.4 ;
      RECT  1475.9 851.2 1480.7 853.4 ;
      RECT  1486.7 851.2 1491.5 853.4 ;
      RECT  1497.5 851.2 1502.3 853.4 ;
      RECT  1508.3 851.2 1513.1 853.4 ;
      RECT  1519.1 851.2 1523.9 853.4 ;
      RECT  1529.9 851.2 1534.7 853.4 ;
      RECT  1540.7 851.2 1545.5 853.4 ;
      RECT  1551.5 851.2 1556.3 853.4 ;
      RECT  1562.3 851.2 1567.1 853.4 ;
      RECT  1573.1 851.2 1577.9 853.4 ;
      RECT  1583.9 851.2 1588.7 853.4 ;
      RECT  1594.7 851.2 1599.5 853.4 ;
      RECT  1605.5 851.2 1610.3 853.4 ;
      RECT  1616.3 851.2 1621.1 853.4 ;
      RECT  1627.1 851.2 1631.9 853.4 ;
      RECT  1637.9 851.2 1642.7 853.4 ;
      RECT  1648.7 851.2 1653.5 853.4 ;
      RECT  1659.5 851.2 1664.3 853.4 ;
      RECT  1670.3 851.2 1675.1 853.4 ;
      RECT  1681.1 851.2 1685.9 853.4 ;
      RECT  1691.9 851.2 1696.7 853.4 ;
      RECT  1702.7 851.2 1707.5 853.4 ;
      RECT  1713.5 851.2 1718.3 853.4 ;
      RECT  1724.3 851.2 1729.1 853.4 ;
      RECT  1735.1 851.2 1739.9 853.4 ;
      RECT  1745.9 851.2 1750.7 853.4 ;
      RECT  1756.7 851.2 1761.5 853.4 ;
      RECT  1767.5 851.2 1772.3 853.4 ;
      RECT  1778.3 851.2 2104.6 853.4 ;
      RECT  8.4 1.4 273.0 3.6 ;
      RECT  3047.6 1.4 3076.4 3.6 ;
      RECT  2157.0 851.2 3076.4 853.4 ;
      RECT  2157.0 3.6 3064.4 9.6 ;
      RECT  2157.0 9.6 3064.4 845.2 ;
      RECT  2157.0 845.2 3064.4 851.2 ;
      RECT  3064.4 3.6 3075.2 9.6 ;
      RECT  3064.4 845.2 3075.2 851.2 ;
      RECT  3075.2 3.6 3076.4 9.6 ;
      RECT  3075.2 9.6 3076.4 845.2 ;
      RECT  3075.2 845.2 3076.4 851.2 ;
      RECT  8.4 3.6 9.6 9.6 ;
      RECT  8.4 9.6 9.6 845.2 ;
      RECT  8.4 845.2 9.6 853.4 ;
      RECT  9.6 3.6 20.4 9.6 ;
      RECT  9.6 845.2 20.4 853.4 ;
      RECT  20.4 3.6 273.0 9.6 ;
      RECT  20.4 9.6 273.0 845.2 ;
      RECT  20.4 845.2 273.0 853.4 ;
   END
END    sram_128x32_1r1w
END    LIBRARY
